VERSION 5.7 ;
  NOWIREEXTENSIONATPIN ON ;
  DIVIDERCHAR "/" ;
  BUSBITCHARS "[]" ;
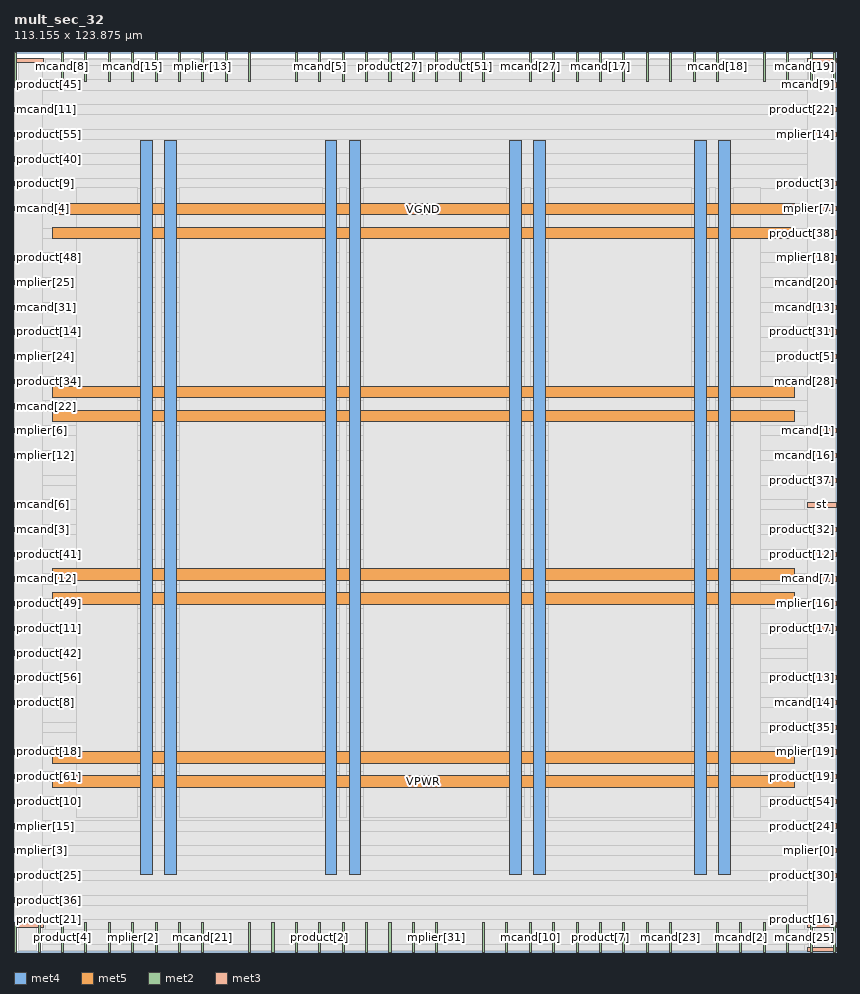
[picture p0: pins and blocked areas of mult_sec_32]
MACRO mult_sec_32
  CLASS BLOCK ;
  FOREIGN mult_sec_32 ;
  ORIGIN 0.000 0.000 ;
  SIZE 113.155 BY 123.875 ;
  PIN VGND
    DIRECTION INOUT ;
    USE GROUND ;
    PORT
      LAYER met4 ;
        RECT 20.725 10.640 22.325 111.760 ;
    END
    PORT
      LAYER met4 ;
        RECT 46.140 10.640 47.740 111.760 ;
    END
    PORT
      LAYER met4 ;
        RECT 71.555 10.640 73.155 111.760 ;
    END
    PORT
      LAYER met4 ;
        RECT 96.970 10.640 98.570 111.760 ;
    END
    PORT
      LAYER met5 ;
        RECT 5.280 25.960 107.420 27.560 ;
    END
    PORT
      LAYER met5 ;
        RECT 5.280 51.120 107.420 52.720 ;
    END
    PORT
      LAYER met5 ;
        RECT 5.280 76.280 107.420 77.880 ;
    END
    PORT
      LAYER met5 ;
        RECT 5.280 101.440 107.420 103.040 ;
    END
  END VGND
  PIN VPWR
    DIRECTION INOUT ;
    USE POWER ;
    PORT
      LAYER met4 ;
        RECT 17.425 10.640 19.025 111.760 ;
    END
    PORT
      LAYER met4 ;
        RECT 42.840 10.640 44.440 111.760 ;
    END
    PORT
      LAYER met4 ;
        RECT 68.255 10.640 69.855 111.760 ;
    END
    PORT
      LAYER met4 ;
        RECT 93.670 10.640 95.270 111.760 ;
    END
    PORT
      LAYER met5 ;
        RECT 5.280 22.660 107.420 24.260 ;
    END
    PORT
      LAYER met5 ;
        RECT 5.280 47.820 107.420 49.420 ;
    END
    PORT
      LAYER met5 ;
        RECT 5.280 72.980 107.420 74.580 ;
    END
    PORT
      LAYER met5 ;
        RECT 5.280 98.140 107.420 99.740 ;
    END
  END VPWR
  PIN clk
    DIRECTION INPUT ;
    USE SIGNAL ;
    ANTENNAGATEAREA 0.852000 ;
    PORT
      LAYER met2 ;
        RECT 74.150 0.000 74.430 4.000 ;
    END
  END clk
  PIN done
    DIRECTION OUTPUT TRISTATE ;
    USE SIGNAL ;
    ANTENNADIFFAREA 0.795200 ;
    PORT
      LAYER met2 ;
        RECT 32.290 0.000 32.570 4.000 ;
    END
  END done
  PIN mcand[0]
    DIRECTION INPUT ;
    USE SIGNAL ;
    ANTENNAGATEAREA 0.196500 ;
    PORT
      LAYER met2 ;
        RECT 48.390 0.000 48.670 4.000 ;
    END
  END mcand[0]
  PIN mcand[10]
    DIRECTION INPUT ;
    USE SIGNAL ;
    ANTENNAGATEAREA 0.213000 ;
    PORT
      LAYER met2 ;
        RECT 70.930 0.000 71.210 4.000 ;
    END
  END mcand[10]
  PIN mcand[11]
    DIRECTION INPUT ;
    USE SIGNAL ;
    ANTENNAGATEAREA 0.126000 ;
    PORT
      LAYER met3 ;
        RECT 0.000 115.640 4.000 116.240 ;
    END
  END mcand[11]
  PIN mcand[12]
    DIRECTION INPUT ;
    USE SIGNAL ;
    ANTENNAGATEAREA 0.196500 ;
    PORT
      LAYER met3 ;
        RECT 0.000 51.040 4.000 51.640 ;
    END
  END mcand[12]
  PIN mcand[13]
    DIRECTION INPUT ;
    USE SIGNAL ;
    ANTENNAGATEAREA 0.196500 ;
    PORT
      LAYER met3 ;
        RECT 109.155 88.440 113.155 89.040 ;
    END
  END mcand[13]
  PIN mcand[14]
    DIRECTION INPUT ;
    USE SIGNAL ;
    ANTENNAGATEAREA 0.213000 ;
    PORT
      LAYER met3 ;
        RECT 109.155 34.040 113.155 34.640 ;
    END
  END mcand[14]
  PIN mcand[15]
    DIRECTION INPUT ;
    USE SIGNAL ;
    ANTENNAGATEAREA 0.196500 ;
    PORT
      LAYER met2 ;
        RECT 16.190 119.875 16.470 123.875 ;
    END
  END mcand[15]
  PIN mcand[16]
    DIRECTION INPUT ;
    USE SIGNAL ;
    ANTENNAGATEAREA 0.196500 ;
    PORT
      LAYER met3 ;
        RECT 109.155 68.040 113.155 68.640 ;
    END
  END mcand[16]
  PIN mcand[17]
    DIRECTION INPUT ;
    USE SIGNAL ;
    ANTENNAGATEAREA 0.196500 ;
    PORT
      LAYER met2 ;
        RECT 80.590 119.875 80.870 123.875 ;
    END
  END mcand[17]
  PIN mcand[18]
    DIRECTION INPUT ;
    USE SIGNAL ;
    ANTENNAGATEAREA 0.196500 ;
    PORT
      LAYER met2 ;
        RECT 96.690 119.875 96.970 123.875 ;
    END
  END mcand[18]
  PIN mcand[19]
    DIRECTION INPUT ;
    USE SIGNAL ;
    ANTENNAGATEAREA 0.196500 ;
    PORT
      LAYER met2 ;
        RECT 112.790 119.875 113.070 123.875 ;
    END
  END mcand[19]
  PIN mcand[1]
    DIRECTION INPUT ;
    USE SIGNAL ;
    ANTENNAGATEAREA 0.196500 ;
    PORT
      LAYER met3 ;
        RECT 109.155 71.440 113.155 72.040 ;
    END
  END mcand[1]
  PIN mcand[20]
    DIRECTION INPUT ;
    USE SIGNAL ;
    ANTENNAGATEAREA 0.196500 ;
    PORT
      LAYER met3 ;
        RECT 109.155 91.840 113.155 92.440 ;
    END
  END mcand[20]
  PIN mcand[21]
    DIRECTION INPUT ;
    USE SIGNAL ;
    ANTENNAGATEAREA 0.196500 ;
    PORT
      LAYER met2 ;
        RECT 25.850 0.000 26.130 4.000 ;
    END
  END mcand[21]
  PIN mcand[22]
    DIRECTION INPUT ;
    USE SIGNAL ;
    ANTENNAGATEAREA 0.196500 ;
    PORT
      LAYER met3 ;
        RECT 0.000 74.840 4.000 75.440 ;
    END
  END mcand[22]
  PIN mcand[23]
    DIRECTION INPUT ;
    USE SIGNAL ;
    ANTENNAGATEAREA 0.196500 ;
    PORT
      LAYER met2 ;
        RECT 90.250 0.000 90.530 4.000 ;
    END
  END mcand[23]
  PIN mcand[24]
    DIRECTION INPUT ;
    USE SIGNAL ;
    ANTENNAGATEAREA 0.196500 ;
    PORT
      LAYER met2 ;
        RECT 48.390 119.875 48.670 123.875 ;
    END
  END mcand[24]
  PIN mcand[25]
    DIRECTION INPUT ;
    USE SIGNAL ;
    ANTENNAGATEAREA 0.196500 ;
    PORT
      LAYER met2 ;
        RECT 112.790 0.000 113.070 4.000 ;
    END
  END mcand[25]
  PIN mcand[26]
    DIRECTION INPUT ;
    USE SIGNAL ;
    ANTENNAGATEAREA 0.196500 ;
    PORT
      LAYER met3 ;
        RECT 109.155 0.040 113.155 0.640 ;
    END
  END mcand[26]
  PIN mcand[27]
    DIRECTION INPUT ;
    USE SIGNAL ;
    ANTENNAGATEAREA 0.213000 ;
    PORT
      LAYER met2 ;
        RECT 70.930 119.875 71.210 123.875 ;
    END
  END mcand[27]
  PIN mcand[28]
    DIRECTION INPUT ;
    USE SIGNAL ;
    ANTENNAGATEAREA 0.196500 ;
    PORT
      LAYER met3 ;
        RECT 109.155 78.240 113.155 78.840 ;
    END
  END mcand[28]
  PIN mcand[29]
    DIRECTION INPUT ;
    USE SIGNAL ;
    ANTENNAGATEAREA 0.196500 ;
    PORT
      LAYER met2 ;
        RECT 22.630 119.875 22.910 123.875 ;
    END
  END mcand[29]
  PIN mcand[2]
    DIRECTION INPUT ;
    USE SIGNAL ;
    ANTENNAGATEAREA 0.196500 ;
    PORT
      LAYER met2 ;
        RECT 99.910 0.000 100.190 4.000 ;
    END
  END mcand[2]
  PIN mcand[30]
    DIRECTION INPUT ;
    USE SIGNAL ;
    ANTENNAGATEAREA 0.196500 ;
    PORT
      LAYER met2 ;
        RECT 35.510 0.000 35.790 4.000 ;
    END
  END mcand[30]
  PIN mcand[31]
    DIRECTION INPUT ;
    USE SIGNAL ;
    ANTENNAGATEAREA 0.196500 ;
    PORT
      LAYER met3 ;
        RECT 0.000 88.440 4.000 89.040 ;
    END
  END mcand[31]
  PIN mcand[3]
    DIRECTION INPUT ;
    USE SIGNAL ;
    ANTENNAGATEAREA 0.196500 ;
    PORT
      LAYER met3 ;
        RECT 0.000 57.840 4.000 58.440 ;
    END
  END mcand[3]
  PIN mcand[4]
    DIRECTION INPUT ;
    USE SIGNAL ;
    ANTENNAGATEAREA 0.196500 ;
    PORT
      LAYER met3 ;
        RECT 0.000 102.040 4.000 102.640 ;
    END
  END mcand[4]
  PIN mcand[5]
    DIRECTION INPUT ;
    USE SIGNAL ;
    ANTENNAGATEAREA 0.196500 ;
    PORT
      LAYER met2 ;
        RECT 41.950 119.875 42.230 123.875 ;
    END
  END mcand[5]
  PIN mcand[6]
    DIRECTION INPUT ;
    USE SIGNAL ;
    ANTENNAGATEAREA 0.213000 ;
    PORT
      LAYER met3 ;
        RECT 0.000 61.240 4.000 61.840 ;
    END
  END mcand[6]
  PIN mcand[7]
    DIRECTION INPUT ;
    USE SIGNAL ;
    ANTENNAGATEAREA 0.196500 ;
    PORT
      LAYER met3 ;
        RECT 109.155 51.040 113.155 51.640 ;
    END
  END mcand[7]
  PIN mcand[8]
    DIRECTION INPUT ;
    USE SIGNAL ;
    ANTENNAGATEAREA 0.196500 ;
    PORT
      LAYER met2 ;
        RECT 6.530 119.875 6.810 123.875 ;
    END
  END mcand[8]
  PIN mcand[9]
    DIRECTION INPUT ;
    USE SIGNAL ;
    ANTENNAGATEAREA 0.126000 ;
    PORT
      LAYER met3 ;
        RECT 109.155 119.040 113.155 119.640 ;
    END
  END mcand[9]
  PIN mplier[0]
    DIRECTION INPUT ;
    USE SIGNAL ;
    ANTENNAGATEAREA 0.196500 ;
    PORT
      LAYER met3 ;
        RECT 109.155 13.640 113.155 14.240 ;
    END
  END mplier[0]
  PIN mplier[10]
    DIRECTION INPUT ;
    USE SIGNAL ;
    ANTENNAGATEAREA 0.196500 ;
    PORT
      LAYER met2 ;
        RECT 12.970 119.875 13.250 123.875 ;
    END
  END mplier[10]
  PIN mplier[11]
    DIRECTION INPUT ;
    USE SIGNAL ;
    ANTENNAGATEAREA 0.196500 ;
    PORT
      LAYER met2 ;
        RECT 45.170 119.875 45.450 123.875 ;
    END
  END mplier[11]
  PIN mplier[12]
    DIRECTION INPUT ;
    USE SIGNAL ;
    ANTENNAGATEAREA 0.196500 ;
    PORT
      LAYER met3 ;
        RECT 0.000 68.040 4.000 68.640 ;
    END
  END mplier[12]
  PIN mplier[13]
    DIRECTION INPUT ;
    USE SIGNAL ;
    ANTENNAGATEAREA 0.196500 ;
    PORT
      LAYER met2 ;
        RECT 25.850 119.875 26.130 123.875 ;
    END
  END mplier[13]
  PIN mplier[14]
    DIRECTION INPUT ;
    USE SIGNAL ;
    ANTENNAGATEAREA 0.213000 ;
    PORT
      LAYER met3 ;
        RECT 109.155 112.240 113.155 112.840 ;
    END
  END mplier[14]
  PIN mplier[15]
    DIRECTION INPUT ;
    USE SIGNAL ;
    ANTENNAGATEAREA 0.196500 ;
    PORT
      LAYER met3 ;
        RECT 0.000 17.040 4.000 17.640 ;
    END
  END mplier[15]
  PIN mplier[16]
    DIRECTION INPUT ;
    USE SIGNAL ;
    ANTENNAGATEAREA 0.196500 ;
    PORT
      LAYER met3 ;
        RECT 109.155 47.640 113.155 48.240 ;
    END
  END mplier[16]
  PIN mplier[17]
    DIRECTION INPUT ;
    USE SIGNAL ;
    ANTENNAGATEAREA 0.196500 ;
    PORT
      LAYER met2 ;
        RECT 106.350 119.875 106.630 123.875 ;
    END
  END mplier[17]
  PIN mplier[18]
    DIRECTION INPUT ;
    USE SIGNAL ;
    ANTENNAGATEAREA 0.196500 ;
    PORT
      LAYER met3 ;
        RECT 109.155 95.240 113.155 95.840 ;
    END
  END mplier[18]
  PIN mplier[19]
    DIRECTION INPUT ;
    USE SIGNAL ;
    ANTENNAGATEAREA 0.196500 ;
    PORT
      LAYER met3 ;
        RECT 109.155 27.240 113.155 27.840 ;
    END
  END mplier[19]
  PIN mplier[1]
    DIRECTION INPUT ;
    USE SIGNAL ;
    ANTENNAGATEAREA 0.196500 ;
    PORT
      LAYER met2 ;
        RECT 58.050 119.875 58.330 123.875 ;
    END
  END mplier[1]
  PIN mplier[20]
    DIRECTION INPUT ;
    USE SIGNAL ;
    ANTENNAGATEAREA 0.196500 ;
    PORT
      LAYER met2 ;
        RECT 3.310 0.000 3.590 4.000 ;
    END
  END mplier[20]
  PIN mplier[21]
    DIRECTION INPUT ;
    USE SIGNAL ;
    ANTENNAGATEAREA 0.196500 ;
    PORT
      LAYER met2 ;
        RECT 77.370 119.875 77.650 123.875 ;
    END
  END mplier[21]
  PIN mplier[22]
    DIRECTION INPUT ;
    USE SIGNAL ;
    ANTENNAGATEAREA 0.196500 ;
    PORT
      LAYER met2 ;
        RECT 83.810 0.000 84.090 4.000 ;
    END
  END mplier[22]
  PIN mplier[23]
    DIRECTION INPUT ;
    USE SIGNAL ;
    ANTENNAGATEAREA 0.196500 ;
    PORT
      LAYER met2 ;
        RECT 109.570 119.875 109.850 123.875 ;
    END
  END mplier[23]
  PIN mplier[24]
    DIRECTION INPUT ;
    USE SIGNAL ;
    ANTENNAGATEAREA 0.196500 ;
    PORT
      LAYER met3 ;
        RECT 0.000 81.640 4.000 82.240 ;
    END
  END mplier[24]
  PIN mplier[25]
    DIRECTION INPUT ;
    USE SIGNAL ;
    ANTENNAGATEAREA 0.196500 ;
    PORT
      LAYER met3 ;
        RECT 0.000 91.840 4.000 92.440 ;
    END
  END mplier[25]
  PIN mplier[26]
    DIRECTION INPUT ;
    USE SIGNAL ;
    ANTENNAGATEAREA 0.196500 ;
    PORT
      LAYER met2 ;
        RECT 0.090 119.875 0.370 123.875 ;
    END
  END mplier[26]
  PIN mplier[27]
    DIRECTION INPUT ;
    USE SIGNAL ;
    ANTENNAGATEAREA 0.196500 ;
    PORT
      LAYER met2 ;
        RECT 45.170 0.000 45.450 4.000 ;
    END
  END mplier[27]
  PIN mplier[28]
    DIRECTION INPUT ;
    USE SIGNAL ;
    ANTENNAGATEAREA 0.196500 ;
    PORT
      LAYER met2 ;
        RECT 54.830 119.875 55.110 123.875 ;
    END
  END mplier[28]
  PIN mplier[29]
    DIRECTION INPUT ;
    USE SIGNAL ;
    ANTENNAGATEAREA 0.196500 ;
    PORT
      LAYER met2 ;
        RECT 32.290 119.875 32.570 123.875 ;
    END
  END mplier[29]
  PIN mplier[2]
    DIRECTION INPUT ;
    USE SIGNAL ;
    ANTENNAGATEAREA 0.196500 ;
    PORT
      LAYER met2 ;
        RECT 16.190 0.000 16.470 4.000 ;
    END
  END mplier[2]
  PIN mplier[30]
    DIRECTION INPUT ;
    USE SIGNAL ;
    ANTENNAGATEAREA 0.196500 ;
    PORT
      LAYER met3 ;
        RECT 109.155 122.440 113.155 123.040 ;
    END
  END mplier[30]
  PIN mplier[31]
    DIRECTION INPUT ;
    USE SIGNAL ;
    ANTENNAGATEAREA 0.196500 ;
    PORT
      LAYER met2 ;
        RECT 58.050 0.000 58.330 4.000 ;
    END
  END mplier[31]
  PIN mplier[3]
    DIRECTION INPUT ;
    USE SIGNAL ;
    ANTENNAGATEAREA 0.196500 ;
    PORT
      LAYER met3 ;
        RECT 0.000 13.640 4.000 14.240 ;
    END
  END mplier[3]
  PIN mplier[4]
    DIRECTION INPUT ;
    USE SIGNAL ;
    ANTENNAGATEAREA 0.196500 ;
    PORT
      LAYER met2 ;
        RECT 64.490 119.875 64.770 123.875 ;
    END
  END mplier[4]
  PIN mplier[5]
    DIRECTION INPUT ;
    USE SIGNAL ;
    ANTENNAGATEAREA 0.196500 ;
    PORT
      LAYER met2 ;
        RECT 87.030 119.875 87.310 123.875 ;
    END
  END mplier[5]
  PIN mplier[6]
    DIRECTION INPUT ;
    USE SIGNAL ;
    ANTENNAGATEAREA 0.196500 ;
    PORT
      LAYER met3 ;
        RECT 0.000 71.440 4.000 72.040 ;
    END
  END mplier[6]
  PIN mplier[7]
    DIRECTION INPUT ;
    USE SIGNAL ;
    ANTENNAGATEAREA 0.126000 ;
    PORT
      LAYER met3 ;
        RECT 109.155 102.040 113.155 102.640 ;
    END
  END mplier[7]
  PIN mplier[8]
    DIRECTION INPUT ;
    USE SIGNAL ;
    ANTENNAGATEAREA 0.196500 ;
    PORT
      LAYER met2 ;
        RECT 93.470 119.875 93.750 123.875 ;
    END
  END mplier[8]
  PIN mplier[9]
    DIRECTION INPUT ;
    USE SIGNAL ;
    ANTENNAGATEAREA 0.196500 ;
    PORT
      LAYER met2 ;
        RECT 9.750 119.875 10.030 123.875 ;
    END
  END mplier[9]
  PIN product[0]
    DIRECTION OUTPUT TRISTATE ;
    USE SIGNAL ;
    ANTENNADIFFAREA 0.795200 ;
    PORT
      LAYER met2 ;
        RECT 38.730 119.875 39.010 123.875 ;
    END
  END product[0]
  PIN product[10]
    DIRECTION OUTPUT TRISTATE ;
    USE SIGNAL ;
    ANTENNADIFFAREA 0.795200 ;
    PORT
      LAYER met3 ;
        RECT 0.000 20.440 4.000 21.040 ;
    END
  END product[10]
  PIN product[11]
    DIRECTION OUTPUT TRISTATE ;
    USE SIGNAL ;
    ANTENNADIFFAREA 0.795200 ;
    PORT
      LAYER met3 ;
        RECT 0.000 44.240 4.000 44.840 ;
    END
  END product[11]
  PIN product[12]
    DIRECTION OUTPUT TRISTATE ;
    USE SIGNAL ;
    ANTENNADIFFAREA 0.795200 ;
    PORT
      LAYER met3 ;
        RECT 109.155 54.440 113.155 55.040 ;
    END
  END product[12]
  PIN product[13]
    DIRECTION OUTPUT TRISTATE ;
    USE SIGNAL ;
    ANTENNADIFFAREA 0.445500 ;
    PORT
      LAYER met3 ;
        RECT 109.155 37.440 113.155 38.040 ;
    END
  END product[13]
  PIN product[14]
    DIRECTION OUTPUT TRISTATE ;
    USE SIGNAL ;
    ANTENNADIFFAREA 0.795200 ;
    PORT
      LAYER met3 ;
        RECT 0.000 85.040 4.000 85.640 ;
    END
  END product[14]
  PIN product[15]
    DIRECTION OUTPUT TRISTATE ;
    USE SIGNAL ;
    ANTENNADIFFAREA 0.795200 ;
    PORT
      LAYER met2 ;
        RECT 9.750 0.000 10.030 4.000 ;
    END
  END product[15]
  PIN product[16]
    DIRECTION OUTPUT TRISTATE ;
    USE SIGNAL ;
    ANTENNADIFFAREA 0.795200 ;
    PORT
      LAYER met3 ;
        RECT 109.155 3.440 113.155 4.040 ;
    END
  END product[16]
  PIN product[17]
    DIRECTION OUTPUT TRISTATE ;
    USE SIGNAL ;
    ANTENNADIFFAREA 0.445500 ;
    PORT
      LAYER met3 ;
        RECT 109.155 44.240 113.155 44.840 ;
    END
  END product[17]
  PIN product[18]
    DIRECTION OUTPUT TRISTATE ;
    USE SIGNAL ;
    ANTENNADIFFAREA 0.795200 ;
    PORT
      LAYER met3 ;
        RECT 0.000 27.240 4.000 27.840 ;
    END
  END product[18]
  PIN product[19]
    DIRECTION OUTPUT TRISTATE ;
    USE SIGNAL ;
    ANTENNADIFFAREA 0.445500 ;
    PORT
      LAYER met3 ;
        RECT 109.155 23.840 113.155 24.440 ;
    END
  END product[19]
  PIN product[1]
    DIRECTION OUTPUT TRISTATE ;
    USE SIGNAL ;
    ANTENNADIFFAREA 0.795200 ;
    PORT
      LAYER met2 ;
        RECT 103.130 0.000 103.410 4.000 ;
    END
  END product[1]
  PIN product[20]
    DIRECTION OUTPUT TRISTATE ;
    USE SIGNAL ;
    ANTENNADIFFAREA 0.795200 ;
    PORT
      LAYER met2 ;
        RECT 51.610 0.000 51.890 4.000 ;
    END
  END product[20]
  PIN product[21]
    DIRECTION OUTPUT TRISTATE ;
    USE SIGNAL ;
    ANTENNADIFFAREA 0.795200 ;
    PORT
      LAYER met3 ;
        RECT 0.000 3.440 4.000 4.040 ;
    END
  END product[21]
  PIN product[22]
    DIRECTION OUTPUT TRISTATE ;
    USE SIGNAL ;
    ANTENNADIFFAREA 0.795200 ;
    PORT
      LAYER met3 ;
        RECT 109.155 115.640 113.155 116.240 ;
    END
  END product[22]
  PIN product[23]
    DIRECTION OUTPUT TRISTATE ;
    USE SIGNAL ;
    ANTENNADIFFAREA 0.795200 ;
    PORT
      LAYER met2 ;
        RECT 22.630 0.000 22.910 4.000 ;
    END
  END product[23]
  PIN product[24]
    DIRECTION OUTPUT TRISTATE ;
    USE SIGNAL ;
    ANTENNADIFFAREA 0.445500 ;
    PORT
      LAYER met3 ;
        RECT 109.155 17.040 113.155 17.640 ;
    END
  END product[24]
  PIN product[25]
    DIRECTION OUTPUT TRISTATE ;
    USE SIGNAL ;
    ANTENNADIFFAREA 0.795200 ;
    PORT
      LAYER met3 ;
        RECT 0.000 10.240 4.000 10.840 ;
    END
  END product[25]
  PIN product[26]
    DIRECTION OUTPUT TRISTATE ;
    USE SIGNAL ;
    ANTENNADIFFAREA 0.795200 ;
    PORT
      LAYER met2 ;
        RECT 109.570 0.000 109.850 4.000 ;
    END
  END product[26]
  PIN product[27]
    DIRECTION OUTPUT TRISTATE ;
    USE SIGNAL ;
    ANTENNADIFFAREA 0.795200 ;
    PORT
      LAYER met2 ;
        RECT 51.610 119.875 51.890 123.875 ;
    END
  END product[27]
  PIN product[28]
    DIRECTION OUTPUT TRISTATE ;
    USE SIGNAL ;
    ANTENNADIFFAREA 0.795200 ;
    PORT
      LAYER met2 ;
        RECT 87.030 0.000 87.310 4.000 ;
    END
  END product[28]
  PIN product[29]
    DIRECTION OUTPUT TRISTATE ;
    USE SIGNAL ;
    ANTENNADIFFAREA 0.795200 ;
    PORT
      LAYER met2 ;
        RECT 12.970 0.000 13.250 4.000 ;
    END
  END product[29]
  PIN product[2]
    DIRECTION OUTPUT TRISTATE ;
    USE SIGNAL ;
    ANTENNADIFFAREA 0.795200 ;
    PORT
      LAYER met2 ;
        RECT 41.950 0.000 42.230 4.000 ;
    END
  END product[2]
  PIN product[30]
    DIRECTION OUTPUT TRISTATE ;
    USE SIGNAL ;
    ANTENNADIFFAREA 0.795200 ;
    PORT
      LAYER met3 ;
        RECT 109.155 10.240 113.155 10.840 ;
    END
  END product[30]
  PIN product[31]
    DIRECTION OUTPUT TRISTATE ;
    USE SIGNAL ;
    ANTENNADIFFAREA 0.445500 ;
    PORT
      LAYER met3 ;
        RECT 109.155 85.040 113.155 85.640 ;
    END
  END product[31]
  PIN product[32]
    DIRECTION OUTPUT TRISTATE ;
    USE SIGNAL ;
    ANTENNADIFFAREA 0.445500 ;
    PORT
      LAYER met3 ;
        RECT 109.155 57.840 113.155 58.440 ;
    END
  END product[32]
  PIN product[33]
    DIRECTION OUTPUT TRISTATE ;
    USE SIGNAL ;
    ANTENNADIFFAREA 0.795200 ;
    PORT
      LAYER met2 ;
        RECT 96.690 0.000 96.970 4.000 ;
    END
  END product[33]
  PIN product[34]
    DIRECTION OUTPUT TRISTATE ;
    USE SIGNAL ;
    ANTENNADIFFAREA 0.795200 ;
    PORT
      LAYER met3 ;
        RECT 0.000 78.240 4.000 78.840 ;
    END
  END product[34]
  PIN product[35]
    DIRECTION OUTPUT TRISTATE ;
    USE SIGNAL ;
    ANTENNADIFFAREA 0.445500 ;
    PORT
      LAYER met3 ;
        RECT 109.155 30.640 113.155 31.240 ;
    END
  END product[35]
  PIN product[36]
    DIRECTION OUTPUT TRISTATE ;
    USE SIGNAL ;
    ANTENNADIFFAREA 0.795200 ;
    PORT
      LAYER met3 ;
        RECT 0.000 6.840 4.000 7.440 ;
    END
  END product[36]
  PIN product[37]
    DIRECTION OUTPUT TRISTATE ;
    USE SIGNAL ;
    ANTENNADIFFAREA 0.445500 ;
    PORT
      LAYER met3 ;
        RECT 109.155 64.640 113.155 65.240 ;
    END
  END product[37]
  PIN product[38]
    DIRECTION OUTPUT TRISTATE ;
    USE SIGNAL ;
    ANTENNADIFFAREA 0.445500 ;
    PORT
      LAYER met3 ;
        RECT 109.155 98.640 113.155 99.240 ;
    END
  END product[38]
  PIN product[39]
    DIRECTION OUTPUT TRISTATE ;
    USE SIGNAL ;
    ANTENNADIFFAREA 0.795200 ;
    PORT
      LAYER met2 ;
        RECT 106.350 0.000 106.630 4.000 ;
    END
  END product[39]
  PIN product[3]
    DIRECTION OUTPUT TRISTATE ;
    USE SIGNAL ;
    ANTENNADIFFAREA 0.795200 ;
    PORT
      LAYER met3 ;
        RECT 109.155 105.440 113.155 106.040 ;
    END
  END product[3]
  PIN product[40]
    DIRECTION OUTPUT TRISTATE ;
    USE SIGNAL ;
    ANTENNADIFFAREA 0.795200 ;
    PORT
      LAYER met3 ;
        RECT 0.000 108.840 4.000 109.440 ;
    END
  END product[40]
  PIN product[41]
    DIRECTION OUTPUT TRISTATE ;
    USE SIGNAL ;
    ANTENNADIFFAREA 0.795200 ;
    PORT
      LAYER met3 ;
        RECT 0.000 54.440 4.000 55.040 ;
    END
  END product[41]
  PIN product[42]
    DIRECTION OUTPUT TRISTATE ;
    USE SIGNAL ;
    ANTENNADIFFAREA 0.795200 ;
    PORT
      LAYER met3 ;
        RECT 0.000 40.840 4.000 41.440 ;
    END
  END product[42]
  PIN product[43]
    DIRECTION OUTPUT TRISTATE ;
    USE SIGNAL ;
    ANTENNADIFFAREA 0.795200 ;
    PORT
      LAYER met2 ;
        RECT 0.090 0.000 0.370 4.000 ;
    END
  END product[43]
  PIN product[44]
    DIRECTION OUTPUT TRISTATE ;
    USE SIGNAL ;
    ANTENNADIFFAREA 0.795200 ;
    PORT
      LAYER met2 ;
        RECT 77.370 0.000 77.650 4.000 ;
    END
  END product[44]
  PIN product[45]
    DIRECTION OUTPUT TRISTATE ;
    USE SIGNAL ;
    ANTENNADIFFAREA 0.795200 ;
    PORT
      LAYER met3 ;
        RECT 0.000 119.040 4.000 119.640 ;
    END
  END product[45]
  PIN product[46]
    DIRECTION OUTPUT TRISTATE ;
    USE SIGNAL ;
    ANTENNADIFFAREA 0.795200 ;
    PORT
      LAYER met2 ;
        RECT 29.070 119.875 29.350 123.875 ;
    END
  END product[46]
  PIN product[47]
    DIRECTION OUTPUT TRISTATE ;
    USE SIGNAL ;
    ANTENNADIFFAREA 0.795200 ;
    PORT
      LAYER met2 ;
        RECT 74.150 119.875 74.430 123.875 ;
    END
  END product[47]
  PIN product[48]
    DIRECTION OUTPUT TRISTATE ;
    USE SIGNAL ;
    ANTENNADIFFAREA 0.795200 ;
    PORT
      LAYER met3 ;
        RECT 0.000 95.240 4.000 95.840 ;
    END
  END product[48]
  PIN product[49]
    DIRECTION OUTPUT TRISTATE ;
    USE SIGNAL ;
    ANTENNADIFFAREA 0.795200 ;
    PORT
      LAYER met3 ;
        RECT 0.000 47.640 4.000 48.240 ;
    END
  END product[49]
  PIN product[4]
    DIRECTION OUTPUT TRISTATE ;
    USE SIGNAL ;
    ANTENNADIFFAREA 0.795200 ;
    PORT
      LAYER met2 ;
        RECT 6.530 0.000 6.810 4.000 ;
    END
  END product[4]
  PIN product[50]
    DIRECTION OUTPUT TRISTATE ;
    USE SIGNAL ;
    ANTENNADIFFAREA 0.795200 ;
    PORT
      LAYER met2 ;
        RECT 90.250 119.875 90.530 123.875 ;
    END
  END product[50]
  PIN product[51]
    DIRECTION OUTPUT TRISTATE ;
    USE SIGNAL ;
    ANTENNADIFFAREA 0.795200 ;
    PORT
      LAYER met2 ;
        RECT 61.270 119.875 61.550 123.875 ;
    END
  END product[51]
  PIN product[52]
    DIRECTION OUTPUT TRISTATE ;
    USE SIGNAL ;
    ANTENNADIFFAREA 0.795200 ;
    PORT
      LAYER met2 ;
        RECT 54.830 0.000 55.110 4.000 ;
    END
  END product[52]
  PIN product[53]
    DIRECTION OUTPUT TRISTATE ;
    USE SIGNAL ;
    ANTENNADIFFAREA 0.795200 ;
    PORT
      LAYER met2 ;
        RECT 103.130 119.875 103.410 123.875 ;
    END
  END product[53]
  PIN product[54]
    DIRECTION OUTPUT TRISTATE ;
    USE SIGNAL ;
    ANTENNADIFFAREA 0.445500 ;
    PORT
      LAYER met3 ;
        RECT 109.155 20.440 113.155 21.040 ;
    END
  END product[54]
  PIN product[55]
    DIRECTION OUTPUT TRISTATE ;
    USE SIGNAL ;
    ANTENNADIFFAREA 0.795200 ;
    PORT
      LAYER met3 ;
        RECT 0.000 112.240 4.000 112.840 ;
    END
  END product[55]
  PIN product[56]
    DIRECTION OUTPUT TRISTATE ;
    USE SIGNAL ;
    ANTENNADIFFAREA 0.795200 ;
    PORT
      LAYER met3 ;
        RECT 0.000 37.440 4.000 38.040 ;
    END
  END product[56]
  PIN product[57]
    DIRECTION OUTPUT TRISTATE ;
    USE SIGNAL ;
    ANTENNADIFFAREA 0.795200 ;
    PORT
      LAYER met2 ;
        RECT 19.410 0.000 19.690 4.000 ;
    END
  END product[57]
  PIN product[58]
    DIRECTION OUTPUT TRISTATE ;
    USE SIGNAL ;
    ANTENNADIFFAREA 0.795200 ;
    PORT
      LAYER met2 ;
        RECT 38.730 0.000 39.010 4.000 ;
    END
  END product[58]
  PIN product[59]
    DIRECTION OUTPUT TRISTATE ;
    USE SIGNAL ;
    ANTENNADIFFAREA 0.795200 ;
    PORT
      LAYER met2 ;
        RECT 64.490 0.000 64.770 4.000 ;
    END
  END product[59]
  PIN product[5]
    DIRECTION OUTPUT TRISTATE ;
    USE SIGNAL ;
    ANTENNADIFFAREA 0.445500 ;
    PORT
      LAYER met3 ;
        RECT 109.155 81.640 113.155 82.240 ;
    END
  END product[5]
  PIN product[60]
    DIRECTION OUTPUT TRISTATE ;
    USE SIGNAL ;
    ANTENNADIFFAREA 0.795200 ;
    PORT
      LAYER met2 ;
        RECT 67.710 0.000 67.990 4.000 ;
    END
  END product[60]
  PIN product[61]
    DIRECTION OUTPUT TRISTATE ;
    USE SIGNAL ;
    ANTENNADIFFAREA 0.795200 ;
    PORT
      LAYER met3 ;
        RECT 0.000 23.840 4.000 24.440 ;
    END
  END product[61]
  PIN product[62]
    DIRECTION OUTPUT TRISTATE ;
    USE SIGNAL ;
    ANTENNADIFFAREA 0.795200 ;
    PORT
      LAYER met2 ;
        RECT 83.810 119.875 84.090 123.875 ;
    END
  END product[62]
  PIN product[63]
    DIRECTION OUTPUT TRISTATE ;
    USE SIGNAL ;
    ANTENNADIFFAREA 0.795200 ;
    PORT
      LAYER met3 ;
        RECT 0.000 122.440 4.000 123.040 ;
    END
  END product[63]
  PIN product[6]
    DIRECTION OUTPUT TRISTATE ;
    USE SIGNAL ;
    ANTENNADIFFAREA 0.795200 ;
    PORT
      LAYER met2 ;
        RECT 19.410 119.875 19.690 123.875 ;
    END
  END product[6]
  PIN product[7]
    DIRECTION OUTPUT TRISTATE ;
    USE SIGNAL ;
    ANTENNADIFFAREA 0.795200 ;
    PORT
      LAYER met2 ;
        RECT 80.590 0.000 80.870 4.000 ;
    END
  END product[7]
  PIN product[8]
    DIRECTION OUTPUT TRISTATE ;
    USE SIGNAL ;
    ANTENNADIFFAREA 0.795200 ;
    PORT
      LAYER met3 ;
        RECT 0.000 34.040 4.000 34.640 ;
    END
  END product[8]
  PIN product[9]
    DIRECTION OUTPUT TRISTATE ;
    USE SIGNAL ;
    ANTENNADIFFAREA 0.795200 ;
    PORT
      LAYER met3 ;
        RECT 0.000 105.440 4.000 106.040 ;
    END
  END product[9]
  PIN st
    DIRECTION INPUT ;
    USE SIGNAL ;
    ANTENNAGATEAREA 0.213000 ;
    PORT
      LAYER met3 ;
        RECT 109.155 61.240 113.155 61.840 ;
    END
  END st
  OBS
      LAYER li1 ;
        RECT 5.520 10.795 107.180 111.605 ;
      LAYER met1 ;
        RECT 0.070 7.180 113.090 112.160 ;
      LAYER met2 ;
        RECT 0.650 119.595 6.250 122.925 ;
        RECT 7.090 119.595 9.470 122.925 ;
        RECT 10.310 119.595 12.690 122.925 ;
        RECT 13.530 119.595 15.910 122.925 ;
        RECT 16.750 119.595 19.130 122.925 ;
        RECT 19.970 119.595 22.350 122.925 ;
        RECT 23.190 119.595 25.570 122.925 ;
        RECT 26.410 119.595 28.790 122.925 ;
        RECT 29.630 119.595 32.010 122.925 ;
        RECT 32.850 119.595 38.450 122.925 ;
        RECT 39.290 119.595 41.670 122.925 ;
        RECT 42.510 119.595 44.890 122.925 ;
        RECT 45.730 119.595 48.110 122.925 ;
        RECT 48.950 119.595 51.330 122.925 ;
        RECT 52.170 119.595 54.550 122.925 ;
        RECT 55.390 119.595 57.770 122.925 ;
        RECT 58.610 119.595 60.990 122.925 ;
        RECT 61.830 119.595 64.210 122.925 ;
        RECT 65.050 119.595 70.650 122.925 ;
        RECT 71.490 119.595 73.870 122.925 ;
        RECT 74.710 119.595 77.090 122.925 ;
        RECT 77.930 119.595 80.310 122.925 ;
        RECT 81.150 119.595 83.530 122.925 ;
        RECT 84.370 119.595 86.750 122.925 ;
        RECT 87.590 119.595 89.970 122.925 ;
        RECT 90.810 119.595 93.190 122.925 ;
        RECT 94.030 119.595 96.410 122.925 ;
        RECT 97.250 119.595 102.850 122.925 ;
        RECT 103.690 119.595 106.070 122.925 ;
        RECT 106.910 119.595 109.290 122.925 ;
        RECT 110.130 119.595 112.510 122.925 ;
        RECT 0.100 4.280 113.060 119.595 ;
        RECT 0.650 0.155 3.030 4.280 ;
        RECT 3.870 0.155 6.250 4.280 ;
        RECT 7.090 0.155 9.470 4.280 ;
        RECT 10.310 0.155 12.690 4.280 ;
        RECT 13.530 0.155 15.910 4.280 ;
        RECT 16.750 0.155 19.130 4.280 ;
        RECT 19.970 0.155 22.350 4.280 ;
        RECT 23.190 0.155 25.570 4.280 ;
        RECT 26.410 0.155 32.010 4.280 ;
        RECT 32.850 0.155 35.230 4.280 ;
        RECT 36.070 0.155 38.450 4.280 ;
        RECT 39.290 0.155 41.670 4.280 ;
        RECT 42.510 0.155 44.890 4.280 ;
        RECT 45.730 0.155 48.110 4.280 ;
        RECT 48.950 0.155 51.330 4.280 ;
        RECT 52.170 0.155 54.550 4.280 ;
        RECT 55.390 0.155 57.770 4.280 ;
        RECT 58.610 0.155 64.210 4.280 ;
        RECT 65.050 0.155 67.430 4.280 ;
        RECT 68.270 0.155 70.650 4.280 ;
        RECT 71.490 0.155 73.870 4.280 ;
        RECT 74.710 0.155 77.090 4.280 ;
        RECT 77.930 0.155 80.310 4.280 ;
        RECT 81.150 0.155 83.530 4.280 ;
        RECT 84.370 0.155 86.750 4.280 ;
        RECT 87.590 0.155 89.970 4.280 ;
        RECT 90.810 0.155 96.410 4.280 ;
        RECT 97.250 0.155 99.630 4.280 ;
        RECT 100.470 0.155 102.850 4.280 ;
        RECT 103.690 0.155 106.070 4.280 ;
        RECT 106.910 0.155 109.290 4.280 ;
        RECT 110.130 0.155 112.510 4.280 ;
      LAYER met3 ;
        RECT 4.400 122.040 108.755 122.905 ;
        RECT 3.990 120.040 109.155 122.040 ;
        RECT 4.400 118.640 108.755 120.040 ;
        RECT 3.990 116.640 109.155 118.640 ;
        RECT 4.400 115.240 108.755 116.640 ;
        RECT 3.990 113.240 109.155 115.240 ;
        RECT 4.400 111.840 108.755 113.240 ;
        RECT 3.990 109.840 109.155 111.840 ;
        RECT 4.400 108.440 109.155 109.840 ;
        RECT 3.990 106.440 109.155 108.440 ;
        RECT 4.400 105.040 108.755 106.440 ;
        RECT 3.990 103.040 109.155 105.040 ;
        RECT 4.400 101.640 108.755 103.040 ;
        RECT 3.990 99.640 109.155 101.640 ;
        RECT 3.990 98.240 108.755 99.640 ;
        RECT 3.990 96.240 109.155 98.240 ;
        RECT 4.400 94.840 108.755 96.240 ;
        RECT 3.990 92.840 109.155 94.840 ;
        RECT 4.400 91.440 108.755 92.840 ;
        RECT 3.990 89.440 109.155 91.440 ;
        RECT 4.400 88.040 108.755 89.440 ;
        RECT 3.990 86.040 109.155 88.040 ;
        RECT 4.400 84.640 108.755 86.040 ;
        RECT 3.990 82.640 109.155 84.640 ;
        RECT 4.400 81.240 108.755 82.640 ;
        RECT 3.990 79.240 109.155 81.240 ;
        RECT 4.400 77.840 108.755 79.240 ;
        RECT 3.990 75.840 109.155 77.840 ;
        RECT 4.400 74.440 109.155 75.840 ;
        RECT 3.990 72.440 109.155 74.440 ;
        RECT 4.400 71.040 108.755 72.440 ;
        RECT 3.990 69.040 109.155 71.040 ;
        RECT 4.400 67.640 108.755 69.040 ;
        RECT 3.990 65.640 109.155 67.640 ;
        RECT 3.990 64.240 108.755 65.640 ;
        RECT 3.990 62.240 109.155 64.240 ;
        RECT 4.400 60.840 108.755 62.240 ;
        RECT 3.990 58.840 109.155 60.840 ;
        RECT 4.400 57.440 108.755 58.840 ;
        RECT 3.990 55.440 109.155 57.440 ;
        RECT 4.400 54.040 108.755 55.440 ;
        RECT 3.990 52.040 109.155 54.040 ;
        RECT 4.400 50.640 108.755 52.040 ;
        RECT 3.990 48.640 109.155 50.640 ;
        RECT 4.400 47.240 108.755 48.640 ;
        RECT 3.990 45.240 109.155 47.240 ;
        RECT 4.400 43.840 108.755 45.240 ;
        RECT 3.990 41.840 109.155 43.840 ;
        RECT 4.400 40.440 109.155 41.840 ;
        RECT 3.990 38.440 109.155 40.440 ;
        RECT 4.400 37.040 108.755 38.440 ;
        RECT 3.990 35.040 109.155 37.040 ;
        RECT 4.400 33.640 108.755 35.040 ;
        RECT 3.990 31.640 109.155 33.640 ;
        RECT 3.990 30.240 108.755 31.640 ;
        RECT 3.990 28.240 109.155 30.240 ;
        RECT 4.400 26.840 108.755 28.240 ;
        RECT 3.990 24.840 109.155 26.840 ;
        RECT 4.400 23.440 108.755 24.840 ;
        RECT 3.990 21.440 109.155 23.440 ;
        RECT 4.400 20.040 108.755 21.440 ;
        RECT 3.990 18.040 109.155 20.040 ;
        RECT 4.400 16.640 108.755 18.040 ;
        RECT 3.990 14.640 109.155 16.640 ;
        RECT 4.400 13.240 108.755 14.640 ;
        RECT 3.990 11.240 109.155 13.240 ;
        RECT 4.400 9.840 108.755 11.240 ;
        RECT 3.990 7.840 109.155 9.840 ;
        RECT 4.400 6.440 109.155 7.840 ;
        RECT 3.990 4.440 109.155 6.440 ;
        RECT 4.400 3.040 108.755 4.440 ;
        RECT 3.990 1.040 109.155 3.040 ;
        RECT 3.990 0.175 108.755 1.040 ;
      LAYER met4 ;
        RECT 8.575 18.535 17.025 105.225 ;
        RECT 19.425 18.535 20.325 105.225 ;
        RECT 22.725 18.535 42.440 105.225 ;
        RECT 44.840 18.535 45.740 105.225 ;
        RECT 48.140 18.535 67.855 105.225 ;
        RECT 70.255 18.535 71.155 105.225 ;
        RECT 73.555 18.535 93.270 105.225 ;
        RECT 95.670 18.535 96.570 105.225 ;
        RECT 98.970 18.535 102.745 105.225 ;
  END
END mult_sec_32
END LIBRARY

